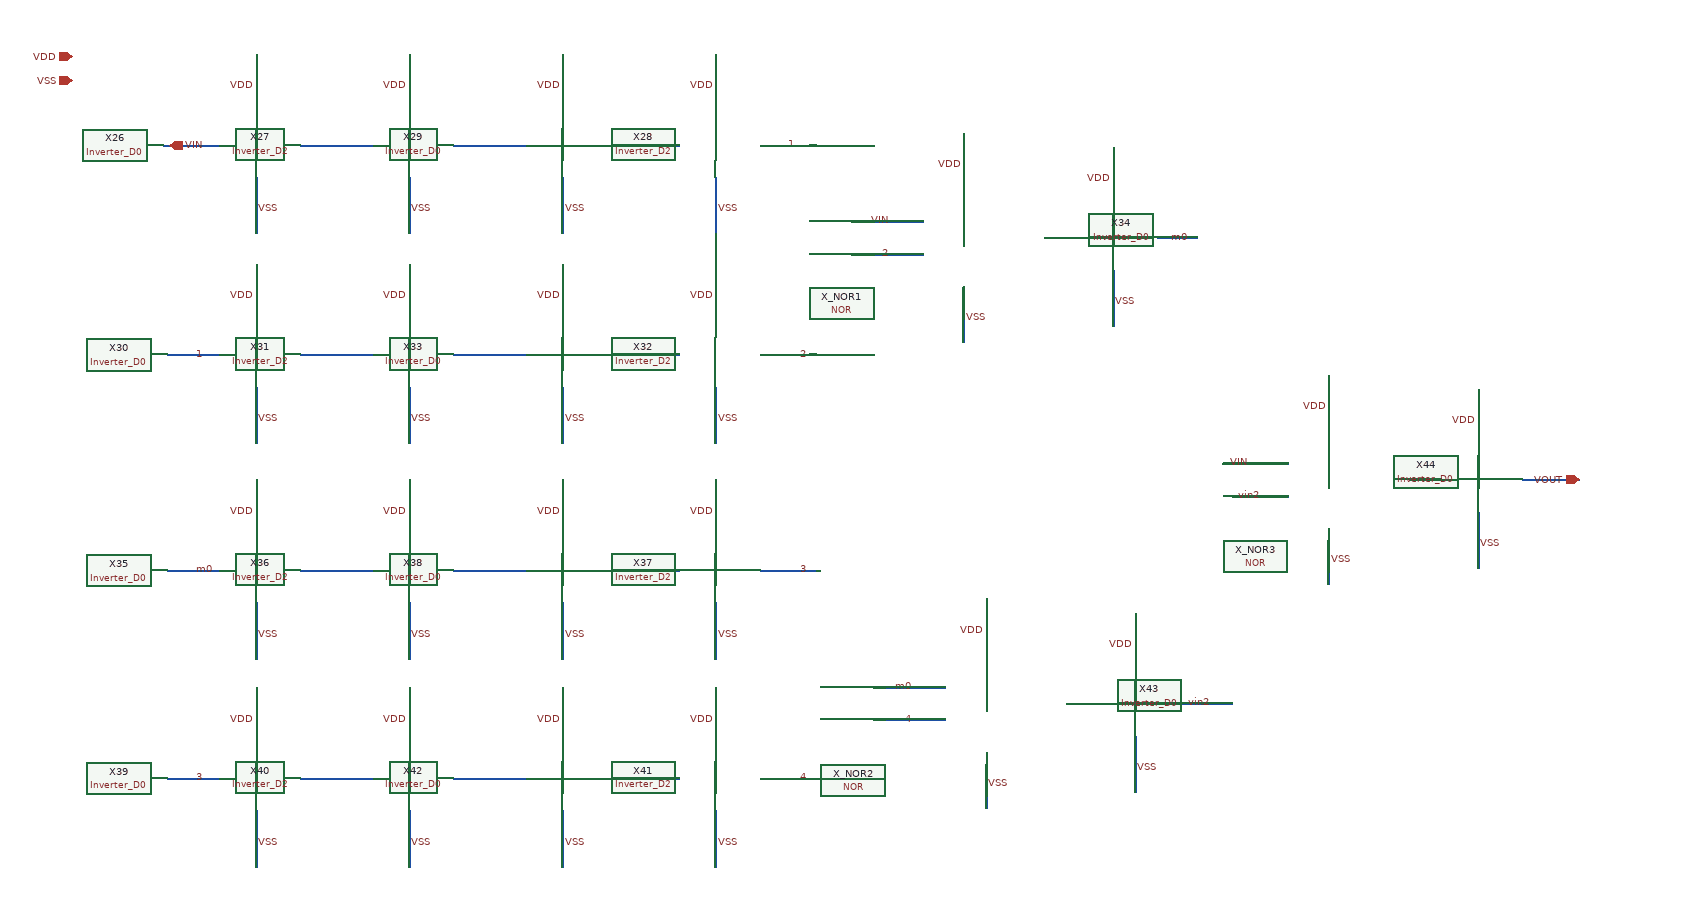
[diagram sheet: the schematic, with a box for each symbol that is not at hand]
v {xschem version=3.0.0 file_version=1.2 }
G {}
K {}
V {}
S {}
E {}
N 2295 -3012.5 2295 -2942.5 {
lab=VDD}
N 2295 -2860 2295 -2790 {
lab=VSS}
N 2350 -2900 2440 -2900 {
lab=#net1}
N 2920 -2900 2990 -2900 {
lab=1}
N 2180 -2900 2250 -2900 {
lab=VIN}
N 2485 -3012.5 2485 -2942.5 {
lab=VDD}
N 2485 -2860 2485 -2790 {
lab=VSS}
N 2540 -2900 2630 -2900 {
lab=#net2}
N 2865 -3012.5 2865 -2942.5 {
lab=VDD}
N 2865 -2860 2865 -2790 {
lab=VSS}
N 2675 -3012.5 2675 -2942.5 {
lab=VDD}
N 2675 -2860 2675 -2790 {
lab=VSS}
N 2730 -2900 2820 -2900 {
lab=#net3}
N 2295 -2752.5 2295 -2682.5 {
lab=VDD}
N 2295 -2600 2295 -2530 {
lab=VSS}
N 2350 -2640 2440 -2640 {
lab=#net4}
N 2485 -2752.5 2485 -2682.5 {
lab=VDD}
N 2485 -2600 2485 -2530 {
lab=VSS}
N 2540 -2640 2630 -2640 {
lab=#net5}
N 2865 -2752.5 2865 -2682.5 {
lab=VDD}
N 2865 -2600 2865 -2530 {
lab=VSS}
N 2675 -2752.5 2675 -2682.5 {
lab=VDD}
N 2675 -2600 2675 -2530 {
lab=VSS}
N 2730 -2640 2820 -2640 {
lab=#net6}
N 2185 -2640 2250 -2640 {
lab=1}
N 2920 -2640 2990 -2640 {
lab=2}
N 3272.5 -2785 3312.5 -2785 {
lab=#net7}
N 3032.5 -2765 3122.5 -2765 {
lab=2}
N 3865 -2485 3935 -2485 {
lab=VOUT}
N 3357.5 -2897.5 3357.5 -2827.5 {
lab=VDD}
N 3357.5 -2745 3357.5 -2675 {
lab=VSS}
N 3032.5 -2805 3122.5 -2805 {
lab=VIN}
N 3172.5 -2915 3172.5 -2845 {
lab=VDD}
N 3172.5 -2725 3172.5 -2655 {
lab=VSS}
N 2295 -2485 2295 -2415 {
lab=VDD}
N 2295 -2332.5 2295 -2262.5 {
lab=VSS}
N 2350 -2372.5 2440 -2372.5 {
lab=#net8}
N 2485 -2485 2485 -2415 {
lab=VDD}
N 2485 -2332.5 2485 -2262.5 {
lab=VSS}
N 2540 -2372.5 2630 -2372.5 {
lab=#net9}
N 2865 -2485 2865 -2415 {
lab=VDD}
N 2865 -2332.5 2865 -2262.5 {
lab=VSS}
N 2675 -2485 2675 -2415 {
lab=VDD}
N 2675 -2332.5 2675 -2262.5 {
lab=VSS}
N 2730 -2372.5 2820 -2372.5 {
lab=#net10}
N 2185 -2372.5 2250 -2372.5 {
lab=m0}
N 2920 -2372.5 2990 -2372.5 {
lab=3}
N 2295 -2227.5 2295 -2157.5 {
lab=VDD}
N 2295 -2075 2295 -2005 {
lab=VSS}
N 2350 -2115 2440 -2115 {
lab=#net11}
N 2485 -2227.5 2485 -2157.5 {
lab=VDD}
N 2485 -2075 2485 -2005 {
lab=VSS}
N 2540 -2115 2630 -2115 {
lab=#net12}
N 2865 -2227.5 2865 -2157.5 {
lab=VDD}
N 2865 -2075 2865 -2005 {
lab=VSS}
N 2675 -2227.5 2675 -2157.5 {
lab=VDD}
N 2675 -2075 2675 -2005 {
lab=VSS}
N 2730 -2115 2820 -2115 {
lab=#net13}
N 2185 -2115 2250 -2115 {
lab=3}
N 2920 -2115 2990 -2115 {
lab=4}
N 3300 -2207.5 3340 -2207.5 {
lab=#net14}
N 3060 -2187.5 3150 -2187.5 {
lab=4}
N 3385 -2320 3385 -2250 {
lab=VDD}
N 3385 -2167.5 3385 -2097.5 {
lab=VSS}
N 3060 -2227.5 3150 -2227.5 {
lab=m0}
N 3200 -2337.5 3200 -2267.5 {
lab=VDD}
N 3200 -2147.5 3200 -2077.5 {
lab=VSS}
N 3725 -2485 3765 -2485 {
lab=#net15}
N 3810 -2597.5 3810 -2527.5 {
lab=VDD}
N 3810 -2445 3810 -2375 {
lab=VSS}
N 3625 -2615 3625 -2545 {
lab=VDD}
N 3625 -2425 3625 -2355 {
lab=VSS}
N 3440 -2207.5 3505 -2207.5 {
lab=vin2}
N 3505 -2465 3575 -2465 {
lab=vin2}
N 3412.5 -2785 3462.5 -2785 {
lab=m0}
N 3492.5 -2505 3575 -2505 {
lab=VIN}
C {devices/lab_wire.sym} 2295 -2972.5 0 0 {name=l4 sig_type=std_logic lab=VDD}
C {devices/lab_wire.sym} 2295 -2820 0 1 {name=l14 sig_type=std_logic lab=VSS}
C {devices/iopin.sym} 2067.5 -3010 0 0 {name=p5 lab=VDD}
C {devices/iopin.sym} 2067.5 -2980 0 0 {name=p6 lab=VSS}
C {devices/iopin.sym} 2187.5 -2900 0 1 {name=p7 lab=VIN}
C {DC_DC_Converter/DELAY_JAWAD/Inverter_D0.sym} 2210 -2900 0 0 {name=X26}
C {DC_DC_Converter/DELAY_JAWAD/Inverter_D2.sym} 2260 -2900 0 0 {name=X27}
C {devices/lab_wire.sym} 2485 -2972.5 0 0 {name=l24 sig_type=std_logic lab=VDD}
C {devices/lab_wire.sym} 2485 -2820 0 1 {name=l34 sig_type=std_logic lab=VSS}
C {DC_DC_Converter/DELAY_JAWAD/Inverter_D2.sym} 2640 -2900 0 0 {name=X28}
C {devices/lab_wire.sym} 2865 -2972.5 0 0 {name=l41 sig_type=std_logic lab=VDD}
C {devices/lab_wire.sym} 2865 -2820 0 1 {name=l46 sig_type=std_logic lab=VSS}
C {devices/lab_wire.sym} 2675 -2972.5 0 0 {name=l80 sig_type=std_logic lab=VDD}
C {devices/lab_wire.sym} 2675 -2820 0 1 {name=l81 sig_type=std_logic lab=VSS}
C {DC_DC_Converter/DELAY_JAWAD/Inverter_D0.sym} 2590 -2900 0 0 {name=X29}
C {devices/lab_wire.sym} 2295 -2712.5 0 0 {name=l82 sig_type=std_logic lab=VDD}
C {devices/lab_wire.sym} 2295 -2560 0 1 {name=l83 sig_type=std_logic lab=VSS}
C {DC_DC_Converter/DELAY_JAWAD/Inverter_D0.sym} 2210 -2640 0 0 {name=X30}
C {DC_DC_Converter/DELAY_JAWAD/Inverter_D2.sym} 2260 -2640 0 0 {name=X31}
C {devices/lab_wire.sym} 2485 -2712.5 0 0 {name=l84 sig_type=std_logic lab=VDD}
C {devices/lab_wire.sym} 2485 -2560 0 1 {name=l85 sig_type=std_logic lab=VSS}
C {DC_DC_Converter/DELAY_JAWAD/Inverter_D2.sym} 2640 -2640 0 0 {name=X32}
C {devices/lab_wire.sym} 2865 -2712.5 0 0 {name=l86 sig_type=std_logic lab=VDD}
C {devices/lab_wire.sym} 2865 -2560 0 1 {name=l87 sig_type=std_logic lab=VSS}
C {devices/lab_wire.sym} 2217.5 -2640 0 1 {name=l88 sig_type=std_logic lab=1}
C {devices/lab_wire.sym} 2675 -2712.5 0 0 {name=l89 sig_type=std_logic lab=VDD}
C {devices/lab_wire.sym} 2675 -2560 0 1 {name=l90 sig_type=std_logic lab=VSS}
C {DC_DC_Converter/DELAY_JAWAD/Inverter_D0.sym} 2590 -2640 0 0 {name=X33}
C {devices/lab_wire.sym} 2952.5 -2900 0 1 {name=l91 sig_type=std_logic lab=1}
C {devices/iopin.sym} 3935 -2485 0 0 {name=p8 lab=VOUT}
C {devices/lab_wire.sym} 3357.5 -2857.5 0 0 {name=l92 sig_type=std_logic lab=VDD}
C {devices/lab_wire.sym} 3357.5 -2705 0 1 {name=l93 sig_type=std_logic lab=VSS}
C {DC_DC_Converter/DELAY_JAWAD/Inverter_D0.sym} 3272.5 -2785 0 0 {name=X34}
C {devices/lab_wire.sym} 2980 -2640 0 0 {name=l94 sig_type=std_logic lab=2}
C {devices/lab_wire.sym} 3082.5 -2765 0 0 {name=l95 sig_type=std_logic lab=2}
C {devices/lab_wire.sym} 3082.5 -2805 0 0 {name=l96 sig_type=std_logic lab=VIN}
C {devices/lab_wire.sym} 3172.5 -2875 0 0 {name=l97 sig_type=std_logic lab=VDD}
C {devices/lab_wire.sym} 3172.5 -2685 0 1 {name=l98 sig_type=std_logic lab=VSS}
C {devices/lab_wire.sym} 2295 -2445 0 0 {name=l99 sig_type=std_logic lab=VDD}
C {devices/lab_wire.sym} 2295 -2292.5 0 1 {name=l100 sig_type=std_logic lab=VSS}
C {DC_DC_Converter/DELAY_JAWAD/Inverter_D0.sym} 2210 -2372.5 0 0 {name=X35}
C {DC_DC_Converter/DELAY_JAWAD/Inverter_D2.sym} 2260 -2372.5 0 0 {name=X36}
C {devices/lab_wire.sym} 2485 -2445 0 0 {name=l101 sig_type=std_logic lab=VDD}
C {devices/lab_wire.sym} 2485 -2292.5 0 1 {name=l102 sig_type=std_logic lab=VSS}
C {DC_DC_Converter/DELAY_JAWAD/Inverter_D2.sym} 2640 -2372.5 0 0 {name=X37}
C {devices/lab_wire.sym} 2865 -2445 0 0 {name=l103 sig_type=std_logic lab=VDD}
C {devices/lab_wire.sym} 2865 -2292.5 0 1 {name=l104 sig_type=std_logic lab=VSS}
C {devices/lab_wire.sym} 2217.5 -2372.5 0 1 {name=l105 sig_type=std_logic lab=m0}
C {devices/lab_wire.sym} 2675 -2445 0 0 {name=l106 sig_type=std_logic lab=VDD}
C {devices/lab_wire.sym} 2675 -2292.5 0 1 {name=l107 sig_type=std_logic lab=VSS}
C {DC_DC_Converter/DELAY_JAWAD/Inverter_D0.sym} 2590 -2372.5 0 0 {name=X38}
C {devices/lab_wire.sym} 2980 -2372.5 0 0 {name=l108 sig_type=std_logic lab=3}
C {devices/lab_wire.sym} 2295 -2187.5 0 0 {name=l109 sig_type=std_logic lab=VDD}
C {devices/lab_wire.sym} 2295 -2035 0 1 {name=l110 sig_type=std_logic lab=VSS}
C {DC_DC_Converter/DELAY_JAWAD/Inverter_D0.sym} 2210 -2115 0 0 {name=X39}
C {DC_DC_Converter/DELAY_JAWAD/Inverter_D2.sym} 2260 -2115 0 0 {name=X40}
C {devices/lab_wire.sym} 2485 -2187.5 0 0 {name=l111 sig_type=std_logic lab=VDD}
C {devices/lab_wire.sym} 2485 -2035 0 1 {name=l112 sig_type=std_logic lab=VSS}
C {DC_DC_Converter/DELAY_JAWAD/Inverter_D2.sym} 2640 -2115 0 0 {name=X41}
C {devices/lab_wire.sym} 2865 -2187.5 0 0 {name=l113 sig_type=std_logic lab=VDD}
C {devices/lab_wire.sym} 2865 -2035 0 1 {name=l114 sig_type=std_logic lab=VSS}
C {devices/lab_wire.sym} 2217.5 -2115 0 1 {name=l115 sig_type=std_logic lab=3}
C {devices/lab_wire.sym} 2675 -2187.5 0 0 {name=l116 sig_type=std_logic lab=VDD}
C {devices/lab_wire.sym} 2675 -2035 0 1 {name=l117 sig_type=std_logic lab=VSS}
C {DC_DC_Converter/DELAY_JAWAD/Inverter_D0.sym} 2590 -2115 0 0 {name=X42}
C {devices/lab_wire.sym} 2980 -2115 0 0 {name=l118 sig_type=std_logic lab=4}
C {devices/lab_wire.sym} 3385 -2280 0 0 {name=l119 sig_type=std_logic lab=VDD}
C {devices/lab_wire.sym} 3385 -2127.5 0 1 {name=l120 sig_type=std_logic lab=VSS}
C {DC_DC_Converter/DELAY_JAWAD/Inverter_D0.sym} 3300 -2207.5 0 0 {name=X43}
C {devices/lab_wire.sym} 3110 -2187.5 0 0 {name=l121 sig_type=std_logic lab=4}
C {devices/lab_wire.sym} 3110 -2227.5 0 0 {name=l122 sig_type=std_logic lab=m0}
C {devices/lab_wire.sym} 3200 -2297.5 0 0 {name=l123 sig_type=std_logic lab=VDD}
C {devices/lab_wire.sym} 3200 -2107.5 0 1 {name=l124 sig_type=std_logic lab=VSS}
C {devices/lab_wire.sym} 3810 -2557.5 0 0 {name=l125 sig_type=std_logic lab=VDD}
C {devices/lab_wire.sym} 3810 -2405 0 1 {name=l126 sig_type=std_logic lab=VSS}
C {DC_DC_Converter/DELAY_JAWAD/Inverter_D0.sym} 3725 -2485 0 0 {name=X44}
C {devices/lab_wire.sym} 3625 -2575 0 0 {name=l127 sig_type=std_logic lab=VDD}
C {devices/lab_wire.sym} 3625 -2385 0 1 {name=l128 sig_type=std_logic lab=VSS}
C {devices/lab_wire.sym} 3452.5 -2785 0 0 {name=l129 sig_type=std_logic lab=m0}
C {DC_DC_Converter/DELAY_JAWAD/NOR.sym} 3102.5 -2715 0 0 {name=X_NOR1}
C {DC_DC_Converter/DELAY_JAWAD/NOR.sym} 3130 -2137.5 0 0 {name=X_NOR2}
C {DC_DC_Converter/DELAY_JAWAD/NOR.sym} 3555 -2415 0 0 {name=X_NOR3}
C {devices/lab_wire.sym} 3480 -2207.5 0 0 {name=l1 sig_type=std_logic lab=vin2}
C {devices/lab_wire.sym} 3542.5 -2465 0 0 {name=l2 sig_type=std_logic lab=vin2}
C {devices/lab_wire.sym} 3527.5 -2505 0 0 {name=l3 sig_type=std_logic lab=VIN}
